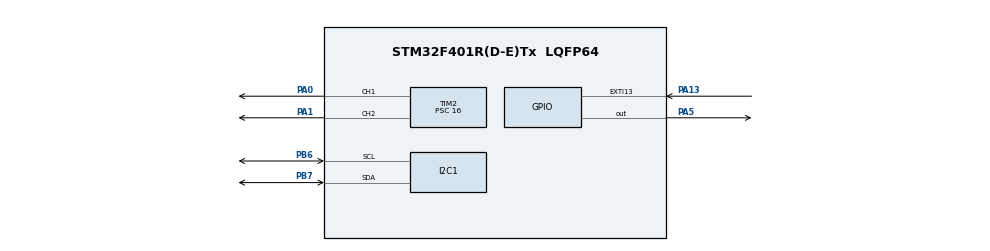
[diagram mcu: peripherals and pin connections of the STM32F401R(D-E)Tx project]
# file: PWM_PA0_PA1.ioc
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Mcu.Family=STM32F4
Mcu.Name=STM32F401R(D-E)Tx
Mcu.Package=LQFP64
NVIC.EXTI15_10_IRQn=true\:0\:0\:false\:false\:true
NVIC.PriorityGroup=NVIC_PRIORITYGROUP_4
NVIC.RCC_IRQn=true\:0\:0\:false\:true\:true\:1
PA0-WKUP.Signal=S_TIM2_CH1_ETR
PA1.Signal=S_TIM2_CH2
PA13.Signal=GPXTI13
PA5.Signal=GPIO_Output
PB6.Mode=I2C
PB6.Signal=I2C1_SCL
PB7.Mode=I2C
PB7.Signal=I2C1_SDA
PH0\ -\ OSC_IN.Mode=HSE-External-Oscillator
PH0\ -\ OSC_IN.Signal=RCC_OSC_IN
PH1\ -\ OSC_OUT.Mode=HSE-External-Oscillator
PH1\ -\ OSC_OUT.Signal=RCC_OSC_OUT
ProjectManager.HeapSize=0x200
ProjectManager.StackSize=0x400
ProjectManager.TargetToolchain=MDK-ARM V5
RCC.48MHZClocksFreq_Value=42000000
RCC.AHBFreq_Value=84000000
RCC.APB1CLKDivider=RCC_HCLK_DIV2
RCC.APB1Freq_Value=42000000
RCC.APB1TimFreq_Value=84000000
RCC.APB2Freq_Value=84000000
RCC.APB2TimFreq_Value=84000000
RCC.CortexFreq_Value=84000000
RCC.HCLKFreq_Value=84000000
RCC.HSE_VALUE=25000000
RCC.HSI_VALUE=16000000
RCC.LSE_VALUE=32768
RCC.PLLM=8
RCC.PLLN=84
RCC.SYSCLKFreq_VALUE=84000000
RCC.SYSCLKSource=RCC_SYSCLKSOURCE_PLLCLK
RCC.VCOOutputFreq_Value=168000000
SH.S_TIM2_CH1_ETR.0=TIM2_CH1,PWM Generation1 CH1
SH.S_TIM2_CH2.0=TIM2_CH2,PWM Generation2 CH2
TIM2.Channel-PWM\ Generation1\ CH1=TIM_CHANNEL_1
TIM2.Channel-PWM\ Generation2\ CH2=TIM_CHANNEL_2
TIM2.Period=100
TIM2.Prescaler=16
TIM2.Pulse-PWM\ Generation1\ CH1=50
TIM2.Pulse-PWM\ Generation2\ CH2=100
VP_TIM2_VS_ClockSourceINT.Mode=Internal
board=PWM_PA0_PA1

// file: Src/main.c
/**
  ******************************************************************************
  * File Name          : main.c
  * Description        : Main program body
  ******************************************************************************
  ** This notice applies to any and all portions of this file
  * that are not between comment pairs USER CODE BEGIN and
  * USER CODE END. Other portions of this file, whether
  * inserted by the user or by software development tools
  * are owned by their respective copyright owners.
  *
  * COPYRIGHT(c) 2017 STMicroelectronics
  *
  * Redistribution and use in source and binary forms, with or without modification,
  * are permitted provided that the following conditions are met:
  *   1. Redistributions of source code must retain the above copyright notice,
  *      this list of conditions and the following disclaimer.
  *   2. Redistributions in binary form must reproduce the above copyright notice,
  *      this list of conditions and the following disclaimer in the documentation
  *      and/or other materials provided with the distribution.
  *   3. Neither the name of STMicroelectronics nor the names of its contributors
  *      may be used to endorse or promote products derived from this software
  *      without specific prior written permission.
  *
  * THIS SOFTWARE IS PROVIDED BY THE COPYRIGHT HOLDERS AND CONTRIBUTORS "AS IS"
  * AND ANY EXPRESS OR IMPLIED WARRANTIES, INCLUDING, BUT NOT LIMITED TO, THE
  * IMPLIED WARRANTIES OF MERCHANTABILITY AND FITNESS FOR A PARTICULAR PURPOSE ARE
  * DISCLAIMED. IN NO EVENT SHALL THE COPYRIGHT HOLDER OR CONTRIBUTORS BE LIABLE
  * FOR ANY DIRECT, INDIRECT, INCIDENTAL, SPECIAL, EXEMPLARY, OR CONSEQUENTIAL
  * DAMAGES (INCLUDING, BUT NOT LIMITED TO, PROCUREMENT OF SUBSTITUTE GOODS OR
  * SERVICES; LOSS OF USE, DATA, OR PROFITS; OR BUSINESS INTERRUPTION) HOWEVER
  * CAUSED AND ON ANY THEORY OF LIABILITY, WHETHER IN CONTRACT, STRICT LIABILITY,
  * OR TORT (INCLUDING NEGLIGENCE OR OTHERWISE) ARISING IN ANY WAY OUT OF THE USE
  * OF THIS SOFTWARE, EVEN IF ADVISED OF THE POSSIBILITY OF SUCH DAMAGE.
  *
  ******************************************************************************
  */
#include "main.h"
#include "stm32f4xx_hal.h"

I2C_HandleTypeDef hi2c1;

TIM_HandleTypeDef htim2;

/* USER CODE BEGIN PV */
/* Private variables ---------------------------------------------------------*/

/* USER CODE END PV */

void SystemClock_Config(void);
static void MX_GPIO_Init(void);
static void MX_TIM2_Init(void);
static void MX_I2C1_Init(void);
static void MX_NVIC_Init(void);

void HAL_TIM_MspPostInit(TIM_HandleTypeDef *htim);

/* USER CODE BEGIN PFP */
/* Private function prototypes -----------------------------------------------*/

/* USER CODE END PFP */

int main(void)
{

  /* MCU Configuration----------------------------------------------------------*/

  /* Reset of all peripherals, Initializes the Flash interface and the Systick. */
  HAL_Init();

  /* Configure the system clock */
  SystemClock_Config();

  /* Initialize all configured peripherals */
  MX_GPIO_Init();
  MX_TIM2_Init();
  MX_I2C1_Init();

  /* Initialize interrupts */
  MX_NVIC_Init();

  /* USER CODE BEGIN 2 */
HAL_TIM_PWM_Start(&htim2, TIM_CHANNEL_1); //Start Timer2 ch1
HAL_TIM_PWM_Start(&htim2, TIM_CHANNEL_2);//start Timer2 Ch12

  /* USER CODE END 2 */

  /* Infinite loop */
  while (1)
  {

  /* USER CODE BEGIN 3 */
HAL_GPIO_WritePin(GPIOA, GPIO_PIN_5, HAL_GPIO_ReadPin(GPIOA, GPIO_PIN_0)); //Mapping PWM_CH1 PA0 to onboard LED on PA5
  }
  /* USER CODE END 3 */

}

/** System Clock Configuration
*/
void SystemClock_Config(void)
{

  RCC_OscInitTypeDef RCC_OscInitStruct;
  RCC_ClkInitTypeDef RCC_ClkInitStruct;

    /**Configure the main internal regulator output voltage
    */
  __HAL_RCC_PWR_CLK_ENABLE();

  __HAL_PWR_VOLTAGESCALING_CONFIG(PWR_REGULATOR_VOLTAGE_SCALE2);

    /**Initializes the CPU, AHB and APB busses clocks
    */
  RCC_OscInitStruct.OscillatorType = RCC_OSCILLATORTYPE_HSE;
  RCC_OscInitStruct.HSEState = RCC_HSE_ON;
  RCC_OscInitStruct.PLL.PLLState = RCC_PLL_ON;
  RCC_OscInitStruct.PLL.PLLSource = RCC_PLLSOURCE_HSE;
  RCC_OscInitStruct.PLL.PLLM = 12;
  RCC_OscInitStruct.PLL.PLLN = 84;
  RCC_OscInitStruct.PLL.PLLP = RCC_PLLP_DIV4;
  RCC_OscInitStruct.PLL.PLLQ = 4;
  if (HAL_RCC_OscConfig(&RCC_OscInitStruct) != HAL_OK)
  {
    _Error_Handler(__FILE__, __LINE__);
  }

    /**Initializes the CPU, AHB and APB busses clocks
    */
  RCC_ClkInitStruct.ClockType = RCC_CLOCKTYPE_HCLK|RCC_CLOCKTYPE_SYSCLK
                              |RCC_CLOCKTYPE_PCLK1|RCC_CLOCKTYPE_PCLK2;
  RCC_ClkInitStruct.SYSCLKSource = RCC_SYSCLKSOURCE_PLLCLK;
  RCC_ClkInitStruct.AHBCLKDivider = RCC_SYSCLK_DIV1;
  RCC_ClkInitStruct.APB1CLKDivider = RCC_HCLK_DIV2;
  RCC_ClkInitStruct.APB2CLKDivider = RCC_HCLK_DIV1;

  if (HAL_RCC_ClockConfig(&RCC_ClkInitStruct, FLASH_LATENCY_1) != HAL_OK)
  {
    _Error_Handler(__FILE__, __LINE__);
  }

    /**Configure the Systick interrupt time
    */
  HAL_SYSTICK_Config(HAL_RCC_GetHCLKFreq()/1000);

    /**Configure the Systick
    */
  HAL_SYSTICK_CLKSourceConfig(SYSTICK_CLKSOURCE_HCLK);

  /* SysTick_IRQn interrupt configuration */
  HAL_NVIC_SetPriority(SysTick_IRQn, 0, 0);
}

/** NVIC Configuration
*/
static void MX_NVIC_Init(void)
{
  /* RCC_IRQn interrupt configuration */
  HAL_NVIC_SetPriority(RCC_IRQn, 0, 0);
  HAL_NVIC_EnableIRQ(RCC_IRQn);
}

/* I2C1 init function */
static void MX_I2C1_Init(void)
{

  hi2c1.Instance = I2C1;
  hi2c1.Init.ClockSpeed = 100000;
  hi2c1.Init.DutyCycle = I2C_DUTYCYCLE_2;
  hi2c1.Init.OwnAddress1 = 0;
  hi2c1.Init.AddressingMode = I2C_ADDRESSINGMODE_7BIT;
  hi2c1.Init.DualAddressMode = I2C_DUALADDRESS_DISABLE;
  hi2c1.Init.OwnAddress2 = 0;
  hi2c1.Init.GeneralCallMode = I2C_GENERALCALL_DISABLE;
  hi2c1.Init.NoStretchMode = I2C_NOSTRETCH_DISABLE;
  if (HAL_I2C_Init(&hi2c1) != HAL_OK)
  {
    _Error_Handler(__FILE__, __LINE__);
  }

}

/* TIM2 init function */
static void MX_TIM2_Init(void)
{

  TIM_ClockConfigTypeDef sClockSourceConfig;
  TIM_MasterConfigTypeDef sMasterConfig;
  TIM_OC_InitTypeDef sConfigOC;

  htim2.Instance = TIM2;
  htim2.Init.Prescaler = 1385;
  htim2.Init.CounterMode = TIM_COUNTERMODE_UP;
  htim2.Init.Period = 100;
  htim2.Init.ClockDivision = TIM_CLOCKDIVISION_DIV1;
  if (HAL_TIM_Base_Init(&htim2) != HAL_OK)
  {
    _Error_Handler(__FILE__, __LINE__);
  }

  sClockSourceConfig.ClockSource = TIM_CLOCKSOURCE_INTERNAL;
  if (HAL_TIM_ConfigClockSource(&htim2, &sClockSourceConfig) != HAL_OK)
  {
    _Error_Handler(__FILE__, __LINE__);
  }

  if (HAL_TIM_PWM_Init(&htim2) != HAL_OK)
  {
    _Error_Handler(__FILE__, __LINE__);
  }

  sMasterConfig.MasterOutputTrigger = TIM_TRGO_RESET;
  sMasterConfig.MasterSlaveMode = TIM_MASTERSLAVEMODE_DISABLE;
  if (HAL_TIMEx_MasterConfigSynchronization(&htim2, &sMasterConfig) != HAL_OK)
  {
    _Error_Handler(__FILE__, __LINE__);
  }

  sConfigOC.OCMode = TIM_OCMODE_PWM1;
  sConfigOC.Pulse = 90;
  sConfigOC.OCPolarity = TIM_OCPOLARITY_HIGH;
  sConfigOC.OCFastMode = TIM_OCFAST_DISABLE;
  if (HAL_TIM_PWM_ConfigChannel(&htim2, &sConfigOC, TIM_CHANNEL_1) != HAL_OK)
  {
    _Error_Handler(__FILE__, __LINE__);
  }

  if (HAL_TIM_PWM_ConfigChannel(&htim2, &sConfigOC, TIM_CHANNEL_2) != HAL_OK)
  {
    _Error_Handler(__FILE__, __LINE__);
  }

  HAL_TIM_MspPostInit(&htim2);

}

/** Configure pins as
        * Analog
        * Input
        * Output
        * EVENT_OUT
        * EXTI
*/
static void MX_GPIO_Init(void)
{

  GPIO_InitTypeDef GPIO_InitStruct;

  /* GPIO Ports Clock Enable */
  __HAL_RCC_GPIOH_CLK_ENABLE();
  __HAL_RCC_GPIOA_CLK_ENABLE();
  __HAL_RCC_GPIOB_CLK_ENABLE();

  /*Configure GPIO pin Output Level */
  HAL_GPIO_WritePin(GPIOA, GPIO_PIN_5, GPIO_PIN_RESET);

  /*Configure GPIO pin : PA5 */
  GPIO_InitStruct.Pin = GPIO_PIN_5;
  GPIO_InitStruct.Mode = GPIO_MODE_OUTPUT_PP;
  GPIO_InitStruct.Pull = GPIO_NOPULL;
  GPIO_InitStruct.Speed = GPIO_SPEED_FREQ_LOW;
  HAL_GPIO_Init(GPIOA, &GPIO_InitStruct);

}

/* USER CODE BEGIN 4 */
//void HAL_GPIO_EXTI_Callback(uint16_t GPIO_Pin)
//{
//	if(val==0){
//	val++;
//	TIM4->CCR1=65535/100*1;
//	}
//	else if(val==1){
//	val++;
//	TIM4->CCR1=65535/100*10;
//	}
//	else if(val==2){
//	val++;
//	TIM4->CCR1=65535/100*50;
//	}
//	else if(val==3){
//	val++;
//	TIM4->CCR1=65535/100*100;
//	}
//}
/* USER CODE END 4 */

void _Error_Handler(char * file, int line)
{
  while(1)
  {
  }
}

/************************ (C) COPYRIGHT STMicroelectronics *****END OF FILE****/
